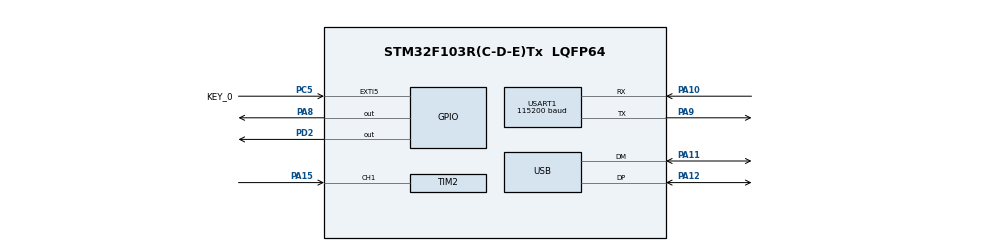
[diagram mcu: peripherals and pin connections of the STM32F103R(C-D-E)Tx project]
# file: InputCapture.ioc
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Mcu.Family=STM32F1
Mcu.Name=STM32F103R(C-D-E)Tx
Mcu.Package=LQFP64
NVIC.EXTI9_5_IRQn=true\:2\:0\:true\:false\:true\:true\:true\:true
NVIC.PriorityGroup=NVIC_PRIORITYGROUP_4
NVIC.TIM2_IRQn=true\:2\:0\:true\:false\:true\:true\:true\:true
NVIC.USB_LP_CAN1_RX0_IRQn=true\:0\:0\:false\:false\:true\:false\:true\:true
PA10.Mode=Asynchronous
PA10.Signal=USART1_RX
PA11.Mode=Device
PA11.Signal=USB_DM
PA12.Mode=Device
PA12.Signal=USB_DP
PA13.Mode=Serial_Wire
PA13.Signal=SYS_JTMS-SWDIO
PA14.Mode=Serial_Wire
PA14.Signal=SYS_JTCK-SWCLK
PA15.Signal=S_TIM2_CH1_ETR
PA8.Signal=GPIO_Output
PA9.Mode=Asynchronous
PA9.Signal=USART1_TX
PC5.GPIO_Label=KEY_0
PC5.GPIO_ModeDefaultEXTI=GPIO_MODE_IT_RISING_FALLING
PC5.GPIO_PuPd=GPIO_PULLUP
PC5.Signal=GPXTI5
PD0-OSC_IN.Mode=HSE-External-Oscillator
PD0-OSC_IN.Signal=RCC_OSC_IN
PD1-OSC_OUT.Mode=HSE-External-Oscillator
PD1-OSC_OUT.Signal=RCC_OSC_OUT
PD2.Signal=GPIO_Output
ProjectManager.HeapSize=0x200
ProjectManager.StackSize=0x400
ProjectManager.TargetToolchain=MDK-ARM V5
RCC.AHBFreq_Value=48000000
RCC.APB1CLKDivider=RCC_HCLK_DIV2
RCC.APB1Freq_Value=24000000
RCC.APB1TimFreq_Value=48000000
RCC.APB2Freq_Value=48000000
RCC.APB2TimFreq_Value=48000000
RCC.HCLKFreq_Value=48000000
RCC.PLLMUL=RCC_PLL_MUL6
RCC.PLLSourceVirtual=RCC_PLLSOURCE_HSE
RCC.SYSCLKFreq_VALUE=48000000
RCC.SYSCLKSource=RCC_SYSCLKSOURCE_PLLCLK
RCC.USBFreq_Value=48000000
SH.S_TIM2_CH1_ETR.0=TIM2_CH1,Input_Capture1_from_TI1
TIM2.Channel-Input_Capture1_from_TI1=TIM_CHANNEL_1
USART1.BaudRate=115200
USART1.VirtualMode=VM_ASYNC
USB_DEVICE.CLASS_NAME_FS=HID
USB_DEVICE.VirtualMode=Hid
USB_DEVICE.VirtualModeFS=Hid_FS
VP_TIM2_VS_ClockSourceINT.Mode=Internal
VP_USB_DEVICE_VS_USB_DEVICE_HID_FS.Mode=HID_FS
board=custom

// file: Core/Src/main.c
/* USER CODE BEGIN Header */
/**
  ******************************************************************************
  * @file           : main.c
  * @brief          : Main program body
  ******************************************************************************
  * @attention
  *
  * Copyright (c) 2023 STMicroelectronics.
  * All rights reserved.
  *
  * This software is licensed under terms that can be found in the LICENSE file
  * in the root directory of this software component.
  * If no LICENSE file comes with this software, it is provided AS-IS.
  *
  ******************************************************************************
  */
/* USER CODE END Header */
#include "main.h"
#include "tim.h"
#include "usart.h"
#include "gpio.h"

/* USER CODE BEGIN Includes */
#include <string.h>
#include <stdio.h>
#include "LCD/lcd.h"
#include "LCD/delay.h"
/* USER CODE END Includes */

/* USER CODE BEGIN PM */
#define LOG_Y_INCREMENT 16
/* USER CODE END PM */

/* USER CODE BEGIN PV */
// max: 18. WILL OVERFLOW IF WENT OUT OF BOUND
int lineNum = 0;
char buf[128] = {0};
//Expected next state of key 0 - PC5 - EXTI5 [9:5]
char key0expState = 0;
/* USER CODE END PV */

void SystemClock_Config(void);
/* USER CODE BEGIN PFP */

/**
 * @brief         : Appends a log message to the LCD screen.
 * @param level   : Severity of the event. 0 -> Verbose(white), 1 -> Info(blue), 2 -> Warning(yellow), 3 -> Error(red), 4 -> Fatal(white on red)
 * @param msg     : Message to be displayed. 116 characters max.
 */
void log(uint8_t level, char msg[]);

/**
 * @brief         : EXTI5 [9:5], callback function for pin PC5 - KEY_0.
 * @param GPIO_Pin: Specifies the pins connected EXTI line.
 * @retval        : None.
 */
void HAL_GPIO_EXTI_Callback(uint16_t GPIO_Pin);

/* USER CODE END PFP */

int main(void)
{

  /* MCU Configuration--------------------------------------------------------*/

  /* Reset of all peripherals, Initializes the Flash interface and the Systick. */
  HAL_Init();

  /* Configure the system clock */
  SystemClock_Config();

  /* Initialize all configured peripherals */
  MX_GPIO_Init();
  MX_USART1_UART_Init();
  MX_TIM2_Init();
  /* USER CODE BEGIN 2 */
  delay_init(72);
  LCD_Init();

  LCD_DisplayOn();
  LCD_Clear(BLACK);
  BACK_COLOR = BLACK;

  log(1, "LCD boot complete");

  HAL_GPIO_WritePin(GPIOD, GPIO_PIN_2, GPIO_PIN_RESET);
  HAL_GPIO_WritePin(GPIOA, GPIO_PIN_8, GPIO_PIN_SET);

  /* USER CODE END 2 */

  /* Infinite loop */
  while (1)
  {

  }
}

void SystemClock_Config(void)
{
  RCC_OscInitTypeDef RCC_OscInitStruct = {0};
  RCC_ClkInitTypeDef RCC_ClkInitStruct = {0};

  /** Initializes the RCC Oscillators according to the specified parameters
  * in the RCC_OscInitTypeDef structure.
  */
  RCC_OscInitStruct.OscillatorType = RCC_OSCILLATORTYPE_HSE;
  RCC_OscInitStruct.HSEState = RCC_HSE_ON;
  RCC_OscInitStruct.HSEPredivValue = RCC_HSE_PREDIV_DIV1;
  RCC_OscInitStruct.HSIState = RCC_HSI_ON;
  RCC_OscInitStruct.PLL.PLLState = RCC_PLL_ON;
  RCC_OscInitStruct.PLL.PLLSource = RCC_PLLSOURCE_HSE;
  RCC_OscInitStruct.PLL.PLLMUL = RCC_PLL_MUL9;
  if (HAL_RCC_OscConfig(&RCC_OscInitStruct) != HAL_OK)
  {
    Error_Handler();
  }

  /** Initializes the CPU, AHB and APB buses clocks
  */
  RCC_ClkInitStruct.ClockType = RCC_CLOCKTYPE_HCLK|RCC_CLOCKTYPE_SYSCLK
                              |RCC_CLOCKTYPE_PCLK1|RCC_CLOCKTYPE_PCLK2;
  RCC_ClkInitStruct.SYSCLKSource = RCC_SYSCLKSOURCE_PLLCLK;
  RCC_ClkInitStruct.AHBCLKDivider = RCC_SYSCLK_DIV1;
  RCC_ClkInitStruct.APB1CLKDivider = RCC_HCLK_DIV2;
  RCC_ClkInitStruct.APB2CLKDivider = RCC_HCLK_DIV1;

  if (HAL_RCC_ClockConfig(&RCC_ClkInitStruct, FLASH_LATENCY_2) != HAL_OK)
  {
    Error_Handler();
  }
}

/* USER CODE BEGIN 4 */

void HAL_GPIO_EXTI_Callback(uint16_t GPIO_Pin) {
  if(GPIO_Pin == GPIO_PIN_5) {
    // HAL_Delay(100);
    if(HAL_GPIO_ReadPin(GPIOC, GPIO_PIN_5) == key0expState) {
      //log(1, "Key 0: valid interaction");
      if(!key0expState) {
        LCD_Clear(BLACK);
        lineNum = 0;
      }
      key0expState = key0expState ? 0 : 1;
    }
    // else {
    //   log(0, "Key 0: invalid interaction - ignored");
    // }
  }
}

void log(uint8_t level, char msg[])
{
  HAL_GPIO_WritePin(GPIOA, GPIO_PIN_8, GPIO_PIN_RESET);
  // TODO: Overflow handler
  if (lineNum >= 18)
  { // 18 lines already present
    for (int8_t l = (strlen(msg) + 11) / 37; l >= 0; l--)
    {
      for (uint16_t i = 10 + LOG_Y_INCREMENT; i < 289; i += LOG_Y_INCREMENT)
      {
        LCD_Fill(10, i - LOG_Y_INCREMENT - 4, 240, i, BLACK);
        for (uint16_t j = 10; j < 230; j++)
        {
          for (uint16_t k = 0; k < 12; k++)
          {
            LCD_Fast_DrawPoint(j, i + k - LOG_Y_INCREMENT, LCD_ReadPoint(j, i + k));
          }
        }
      }
    }
    lineNum = 17 - (strlen(msg) + 11) / 37;
  }
  memset(buf, 0, 128);
  switch (level)
  {
  case 0: // verbose
    sprintf(buf, "%7.3f[V] %s", HAL_GetTick() / 1000.0, msg);
    POINT_COLOR = WHITE;
    break;
  case 1: // debug
    sprintf(buf, "%7.3f[D] %s", HAL_GetTick() / 1000.0, msg);
    POINT_COLOR = BLUE;
    break;
  case 2: // warning
    sprintf(buf, "%7.3f[W] %s", HAL_GetTick() / 1000.0, msg);
    POINT_COLOR = YELLOW;
    break;
  case 3: // error
    sprintf(buf, "%7.3f[E] %s", HAL_GetTick() / 1000.0, msg);
    POINT_COLOR = RED;
    break;
  case 4: // fatal
    sprintf(buf, "%7.3f[F] %s", HAL_GetTick() / 1000.0, msg);
    POINT_COLOR = WHITE;
    BACK_COLOR = RED;
    break;
  }
  LCD_ShowString(10, 10 + lineNum * LOG_Y_INCREMENT, 220, LOG_Y_INCREMENT, 12, (uint8_t *)buf);
  lineNum += strlen(buf) / 37 + 1; // line capacity = 37
  BACK_COLOR = BLACK;
  HAL_GPIO_WritePin(GPIOA, GPIO_PIN_8, GPIO_PIN_SET);
}

/* USER CODE END 4 */

void Error_Handler(void)
{
  __disable_irq();
  while (1)
  {
  }
}
